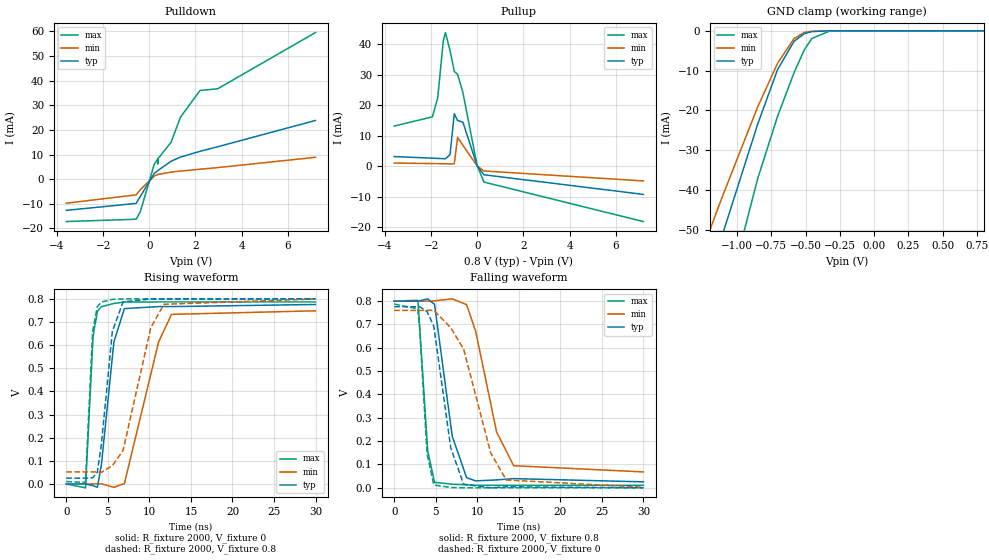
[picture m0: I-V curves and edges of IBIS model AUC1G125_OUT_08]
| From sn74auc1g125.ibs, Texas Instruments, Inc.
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[Model]   AUC1G125_OUT_08
Model_type  3-state
Enable   Active-Low
Vref =   0
Rref =   2000
Cref =   15p
Vmeas =   0.4
| variable   typ   min   max
C_comp   5.50pF   NA   NA
| C_pullup   15.56pF   4.46pF   39.08pF
| C_pulldown   13.26pF   5.97pF   27.73pF
| C_tri-state   10.25pF   5.81pF   19.15pF
[Temperature Range]   40   100   -40
| Ambient temperature   25   85   -40
[Voltage range]   0.8   0.8   0.8
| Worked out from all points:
|   slope of the pulldown table from 0 to 0.12 V, typ, clamps not added: 77 ohm
|   slope of the pullup table from 0 to 0.12 V, typ, clamps not added: 73.2 ohm
|   GND clamp passes 1 mA (typ) near -0.53 V on its own axis
|   rising waveform, R_fixture 2000, V_fixture 0: 20-80 % time 1.31ns typ, 2.66ns min, 611ps max; typ from 0 V to 0.776 V
|   falling waveform, R_fixture 2000, V_fixture 0.8: 20-80 % time 1.7ns typ, 2.63ns min, 793ps max; typ from 0.8 V to 0.025 V
|   rising waveform, R_fixture 2000, V_fixture 0.8: 20-80 % time 1.23ns typ, 2.65ns min, 576ps max; typ from 0.025 V to 0.8 V
|   falling waveform, R_fixture 2000, V_fixture 0: 20-80 % time 1.73ns typ, 3.42ns min, 775ps max; typ from 0.776 V to 0 V
[GND Clamp]
| AUC1G125_OUT_08
|   Voltage   I(typ)   I(min)   I(max)
-3.6V     -338.8mA   -286.3mA   -409.7mA
-1.46V    -91.16mA   -74.57mA   -119.8mA
-1.315V   -74.64mA   -60.86mA   -99.95mA
-1.145V   -55.48mA   -45.09mA   -76.67mA
-1.105V   -51.02mA   -41.44mA   -71.2mA
-850mV    -23.5mA    -19.16mA   -37.2mA
-705mV    -9.778mA   -8.207mA   -21.54mA
-585mV    -2.658mA   -1.97mA    -10.58mA
-510mV    -720.3uA   -415.7uA   -4.835mA
-455mV    -200.7uA   -109.9uA   -1.937mA
-325mV    -4.908uA   -3.982uA   -43.96uA
800mV     202.9pA    373.5pA    160.8pA
[Pulldown]
| AUC1G125_OUT_08
|   Voltage   I(typ)   I(min)   I(max)
-3.6V     -12.63mA   -9.733mA   -17.19mA
-570mV    -9.824mA   -6.355mA   -16.25mA
-390mV    -6.95mA    -4.235mA   -13.17mA
210mV     2.329mA    1.254mA    6.027mA
360mV     3.461mA    1.896mA    8.13mA
365mV     3.499mA    1.915mA    6.143mA
370mV     3.537mA    1.934mA    8.258mA
940mV     7.294mA    2.859mA    14.99mA
1.35V     8.984mA    3.307mA    25.17mA
2.195V    11.32mA    4.051mA    36mA
2.96V     13.17mA    4.715mA    36.72mA
7.2V      23.85mA    8.893mA    59.53mA
[Pullup]
| AUC1G125_OUT_08
|   Voltage   I(typ)   I(min)   I(max)
-3.6V     3.125mA    996.6uA    13.12mA
-1.945V   2.606mA    831.4uA    16.15mA
-1.715V   2.521mA    806.3uA    22.32mA
-1.47V    2.426mA    778.1uA    41.17mA
-1.38V    2.394mA    767.1uA    43.77mA
-1.18V    3.77mA     740.3uA    37.88mA
-995mV    17.17mA    768.8uA    31.03mA
-855mV    14.97mA    9.412mA    30.1mA
-620mV    14.38mA    6.802mA    24.04mA
-5mV      83.77uA    50.86uA    153.9uA
290mV     -2.844mA   -1.602mA   -5.233mA
7.2V      -9.277mA   -4.859mA   -18.18mA
[Ramp]
| AUC1G125_OUT_08
| variable   typ   min   max
dV/dt_r   0.48/1.36E-09   0.46/2.80E-09   0.48/6.35E-10
dV/dt_f   0.47/1.79E-09   0.45/2.80E-09   0.48/8.18E-10
R_load = 2000
[Rising Waveform]
| AUC1G125_OUT_08
R_fixture =   2000
C_fixture =   0
L_fixture =   0
V_fixture =   0
V_fixture_min = 0
V_fixture_max = 0
|   Time   V(typ)   V(min)   V(max)
0s        7.306nV    40.95nV    518.4pV
2.315ns   17.27uV    -26.73uV   -16.58mV
3.22ns    -7.241mV   93.99uV    638.7mV
3.745ns   -14.03mV   535.2uV    746.4mV
4.225ns   82.13mV    553.1uV    766.5mV
5.73ns    614.1mV    -14.37mV   780.2mV
6.995ns   758mV      2.057mV    786.5mV
11.12ns   766.7mV    614.9mV    786.8mV
12.67ns   766.7mV    733.1mV    786.8mV
29.99ns   775.8mV    748.5mV    786.9mV
[Falling Waveform]
| AUC1G125_OUT_08
R_fixture =   2000
C_fixture =   0
L_fixture =   0
V_fixture =   0.8
V_fixture_min = 0.8
V_fixture_max = 0.8
|   Time   V(typ)   V(min)   V(max)
0s        800mV      800mV      800mV
2.86ns    799mV      800mV      802.8mV
4.03ns    809.2mV    799.1mV    158mV
4.855ns   785.7mV    800.6mV    23.39mV
6.99ns    220.5mV    809.1mV    15.39mV
8.715ns   43.21mV    784.5mV    12.92mV
9.805ns   29.61mV    670.4mV    10.86mV
12.33ns   33.74mV    238.4mV    10.59mV
14.38ns   39.29mV    94.64mV    10.59mV
29.99ns   25.48mV    68.02mV    10.6mV
[Rising Waveform]
| AUC1G125_OUT_08
R_fixture =   2000
C_fixture =   0
L_fixture =   0
V_fixture =   0.8
V_fixture_min = 0.8
V_fixture_max = 0.8
|   Time   V(typ)   V(min)   V(max)
0s        25.46mV    52.25mV    10.6mV
2.31ns    25.39mV    52.3mV     6.964mV
3.175ns   26.83mV    52.5mV     660.5mV
3.73ns    49.44mV    51.61mV    765.9mV
4.23ns    173.3mV    50.45mV    786.2mV
5.545ns   659.9mV    79.2mV     798.1mV
6.835ns   786.8mV    144.9mV    800.1mV
10.17ns   799.8mV    674.9mV    799.9mV
11.74ns   799.6mV    776.6mV    799.9mV
29.99ns   800mV      799.5mV    800mV
[Falling Waveform]
| AUC1G125_OUT_08
R_fixture =   2000
C_fixture =   0
L_fixture =   0
V_fixture =   0
V_fixture_min = 0
V_fixture_max = 0
|   Time   V(typ)   V(min)   V(max)
0s        775.8mV    759.7mV    786.9mV
2.82ns    775.3mV    759.6mV    766.8mV
3.065ns   775.8mV    759.5mV    684.3mV
3.955ns   755.1mV    760.3mV    146.1mV
4.765ns   692.1mV    759.9mV    12.62mV
6.805ns   171.5mV    685.8mV    950uV
8.355ns   15.41mV    594.1mV    14.91uV
11.62ns   -233.6uV   149mV      -1.383uV
13.49ns   4.17mV     33.33mV    1.083uV
29.99ns   7.378uV    2.4mV      -5.777nV
